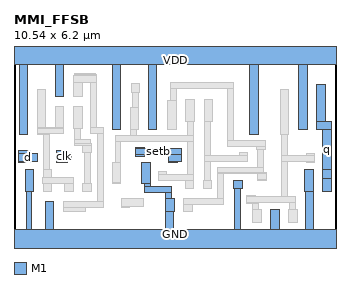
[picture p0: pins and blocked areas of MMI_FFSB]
MACRO MMI_FFSB
	CLASS CORE ;
	FOREIGN MMI_FFSB 0 0 ;
	SIZE 10.54 BY 6.2 ;
	SYMMETRY X Y ;
	SITE CORE1 ;
	PIN d
		DIRECTION input ;
		USE SIGNAL ;
		PORT
			LAYER M1 ;
			RECT 0.16 2.9 0.535 2.98 ;
			LAYER M1 ;
			RECT 0.16 2.62 0.76 2.9 ;
			LAYER M1 ;
			RECT 0.16 2.6 0.535 2.62 ;
		END
		AntennaGateArea 0.3465 ;
	END d
	PIN GND
		DIRECTION inout ;
		USE GROUND ;
		PORT
			LAYER M1 ;
			RECT 0.36 1.65 0.64 2.35 ;
			LAYER M1 ;
			RECT 4.165 1.905 4.455 2.605 ;
			LAYER M1 ;
			RECT 4.26 1.82 4.455 1.905 ;
			LAYER M1 ;
			RECT 0.395 0.42 0.585 1.65 ;
			LAYER M1 ;
			RECT 4.26 1.625 5.13 1.82 ;
			LAYER M1 ;
			RECT 7.175 1.74 7.455 2.02 ;
			LAYER M1 ;
			RECT 4.935 1.43 5.13 1.625 ;
			LAYER M1 ;
			RECT 1.025 0.42 1.305 1.315 ;
			LAYER M1 ;
			RECT 4.935 0.995 5.23 1.43 ;
			LAYER M1 ;
			RECT 4.935 0.42 5.215 0.995 ;
			LAYER M1 ;
			RECT 7.185 0.42 7.38 1.74 ;
			LAYER M1 ;
			RECT 9.48 1.65 9.76 2.35 ;
			LAYER M1 ;
			RECT 8.37 0.42 8.65 1.075 ;
			LAYER M1 ;
			RECT 9.525 0.42 9.76 1.65 ;
			LAYER M1 ;
			RECT 0 -0.42 10.54 0.42 ;
		END
	END GND
	PIN q
		DIRECTION output ;
		USE SIGNAL ;
		PORT
			LAYER M1 ;
			RECT 9.88 3.945 10.16 5.135 ;
			LAYER M1 ;
			RECT 9.88 3.665 10.36 3.945 ;
			LAYER M1 ;
			RECT 9.9 3.66 10.36 3.665 ;
			LAYER M1 ;
			RECT 10.075 2.35 10.36 3.66 ;
			LAYER M1 ;
			RECT 10.07 2.065 10.36 2.35 ;
			LAYER M1 ;
			RECT 10.07 1.65 10.35 2.065 ;
		END
		AntennaDiffArea 0.91245 ;
	END q
	PIN VDD
		DIRECTION inout ;
		USE POWER ;
		PORT
			LAYER M1 ;
			RECT 0 5.78 10.54 6.62 ;
			LAYER M1 ;
			RECT 0.17 3.52 0.45 5.78 ;
			LAYER M1 ;
			RECT 1.35 4.74 1.63 5.78 ;
			LAYER M1 ;
			RECT 3.205 3.675 3.485 5.78 ;
			LAYER M1 ;
			RECT 4.385 3.675 4.665 5.78 ;
			LAYER M1 ;
			RECT 7.7 3.515 7.98 5.78 ;
			LAYER M1 ;
			RECT 9.29 3.665 9.57 5.78 ;
		END
	END VDD
	PIN setb
		DIRECTION input ;
		USE SIGNAL ;
		PORT
			LAYER M1 ;
			RECT 3.98 3.05 4.26 3.085 ;
			LAYER M1 ;
			RECT 3.98 2.86 5.46 3.05 ;
			LAYER M1 ;
			RECT 3.98 2.805 4.26 2.86 ;
			LAYER M1 ;
			RECT 5.045 2.62 5.46 2.86 ;
			LAYER M1 ;
			RECT 5.045 2.59 5.325 2.62 ;
		END
		AntennaGateArea 0.4575 ;
	END setb
	PIN clk
		DIRECTION input ;
		USE CLOCK ;
		PORT
			LAYER M1 ;
			RECT 1.375 2.93 1.75 2.98 ;
			LAYER M1 ;
			RECT 1.375 2.645 1.875 2.93 ;
			LAYER M1 ;
			RECT 1.375 2.6 1.75 2.645 ;
		END
		AntennaGateArea 0.44625 ;
	END clk
	OBS
		LAYER M1 ;
		RECT 0.76 3.745 1.04 4.99 ;
		LAYER M1 ;
		RECT 1.99 5.49 2.46 5.495 ;
		LAYER M1 ;
		RECT 1.99 5.455 2.66 5.49 ;
		LAYER M1 ;
		RECT 1.99 5.44 2.695 5.455 ;
		LAYER M1 ;
		RECT 1.94 5.21 2.695 5.44 ;
		LAYER M1 ;
		RECT 1.94 4.74 2.22 5.21 ;
		LAYER M1 ;
		RECT 1.35 3.745 1.63 4.415 ;
		LAYER M1 ;
		RECT 0.76 3.715 1.63 3.745 ;
		LAYER M1 ;
		RECT 1.94 3.715 2.22 4.415 ;
		LAYER M1 ;
		RECT 2.5 3.75 2.695 5.21 ;
		LAYER M1 ;
		RECT 0.76 3.555 1.625 3.715 ;
		LAYER M1 ;
		RECT 0.76 3.52 1.16 3.555 ;
		LAYER M1 ;
		RECT 0.97 2.35 1.16 3.52 ;
		LAYER M1 ;
		RECT 1.98 3.35 2.17 3.715 ;
		LAYER M1 ;
		RECT 2.5 3.555 2.925 3.75 ;
		LAYER M1 ;
		RECT 3.82 4.885 4.1 5.165 ;
		LAYER M1 ;
		RECT 3.865 4.375 4.055 4.885 ;
		LAYER M1 ;
		RECT 3.795 3.675 4.075 4.375 ;
		LAYER M1 ;
		RECT 5.1 5.01 7.165 5.205 ;
		LAYER M1 ;
		RECT 5.1 4.61 5.29 5.01 ;
		LAYER M1 ;
		RECT 5.01 3.675 5.29 4.61 ;
		LAYER M1 ;
		RECT 5.61 3.935 5.89 4.635 ;
		LAYER M1 ;
		RECT 6.2 3.935 6.48 4.635 ;
		LAYER M1 ;
		RECT 1.98 3.2 2.485 3.35 ;
		LAYER M1 ;
		RECT 1.98 3.155 2.515 3.2 ;
		LAYER M1 ;
		RECT 2.235 2.92 2.515 3.155 ;
		LAYER M1 ;
		RECT 0.95 2.115 1.23 2.35 ;
		LAYER M1 ;
		RECT 0.945 1.92 1.935 2.115 ;
		LAYER M1 ;
		RECT 2.29 1.92 2.485 2.92 ;
		LAYER M1 ;
		RECT 0.95 1.65 1.23 1.92 ;
		LAYER M1 ;
		RECT 1.66 1.64 1.94 1.92 ;
		LAYER M1 ;
		RECT 2.25 1.64 2.53 1.92 ;
		LAYER M1 ;
		RECT 2.73 1.315 2.925 3.555 ;
		LAYER M1 ;
		RECT 3.81 3.475 4 3.675 ;
		LAYER M1 ;
		RECT 5.66 3.475 5.855 3.935 ;
		LAYER M1 ;
		RECT 3.3 3.285 5.855 3.475 ;
		LAYER M1 ;
		RECT 3.3 2.605 3.49 3.285 ;
		LAYER M1 ;
		RECT 3.205 1.955 3.49 2.605 ;
		LAYER M1 ;
		RECT 3.205 1.905 3.485 1.955 ;
		LAYER M1 ;
		RECT 4.705 2.215 4.985 2.3 ;
		LAYER M1 ;
		RECT 5.66 2.215 5.855 3.285 ;
		LAYER M1 ;
		RECT 4.705 2.02 5.855 2.215 ;
		LAYER M1 ;
		RECT 6.21 2.83 6.4 3.935 ;
		LAYER M1 ;
		RECT 6.97 3.31 7.165 5.01 ;
		LAYER M1 ;
		RECT 8.685 3.505 8.965 4.975 ;
		LAYER M1 ;
		RECT 6.97 3.115 8.2 3.31 ;
		LAYER M1 ;
		RECT 7.92 3.03 8.2 3.115 ;
		LAYER M1 ;
		RECT 7.35 2.83 7.63 2.905 ;
		LAYER M1 ;
		RECT 6.21 2.635 7.63 2.83 ;
		LAYER M1 ;
		RECT 6.21 2.02 6.4 2.635 ;
		LAYER M1 ;
		RECT 7.35 2.625 7.63 2.635 ;
		LAYER M1 ;
		RECT 7.94 2.425 8.135 3.03 ;
		LAYER M1 ;
		RECT 6.655 2.28 8.135 2.425 ;
		LAYER M1 ;
		RECT 8.745 2.83 8.935 3.505 ;
		LAYER M1 ;
		RECT 9.535 2.83 9.815 2.885 ;
		LAYER M1 ;
		RECT 8.745 2.635 9.815 2.83 ;
		LAYER M1 ;
		RECT 6.655 2.235 8.225 2.28 ;
		LAYER M1 ;
		RECT 5.58 1.74 5.86 2.02 ;
		LAYER M1 ;
		RECT 6.17 1.74 6.45 2.02 ;
		LAYER M1 ;
		RECT 1.615 1.125 2.925 1.315 ;
		LAYER M1 ;
		RECT 3.505 1.145 4.225 1.425 ;
		LAYER M1 ;
		RECT 1.615 1 2.34 1.125 ;
		LAYER M1 ;
		RECT 3.505 1.115 3.785 1.145 ;
		LAYER M1 ;
		RECT 1.66 0.995 2.34 1 ;
		LAYER M1 ;
		RECT 5.54 1.425 5.82 1.43 ;
		LAYER M1 ;
		RECT 6.655 1.425 6.845 2.235 ;
		LAYER M1 ;
		RECT 7.94 2.05 8.225 2.235 ;
		LAYER M1 ;
		RECT 7.945 2 8.225 2.05 ;
		LAYER M1 ;
		RECT 5.54 1.23 6.845 1.425 ;
		LAYER M1 ;
		RECT 5.54 0.995 5.82 1.23 ;
		LAYER M1 ;
		RECT 7.6 1.47 7.88 1.53 ;
		LAYER M1 ;
		RECT 8.745 1.47 8.935 2.635 ;
		LAYER M1 ;
		RECT 9.535 2.605 9.815 2.635 ;
		LAYER M1 ;
		RECT 7.6 1.28 9.195 1.47 ;
		LAYER M1 ;
		RECT 7.6 1.25 7.975 1.28 ;
		LAYER M1 ;
		RECT 7.78 1.075 7.975 1.25 ;
		LAYER M1 ;
		RECT 9.005 1.075 9.195 1.28 ;
		LAYER M1 ;
		RECT 7.78 0.625 8.06 1.075 ;
		LAYER M1 ;
		RECT 8.96 0.625 9.24 1.075 ;
	END
END MMI_FFSB
